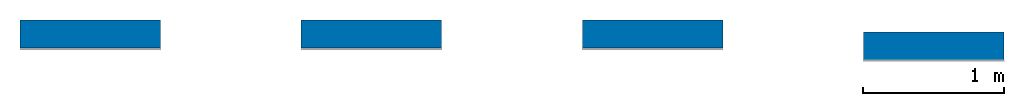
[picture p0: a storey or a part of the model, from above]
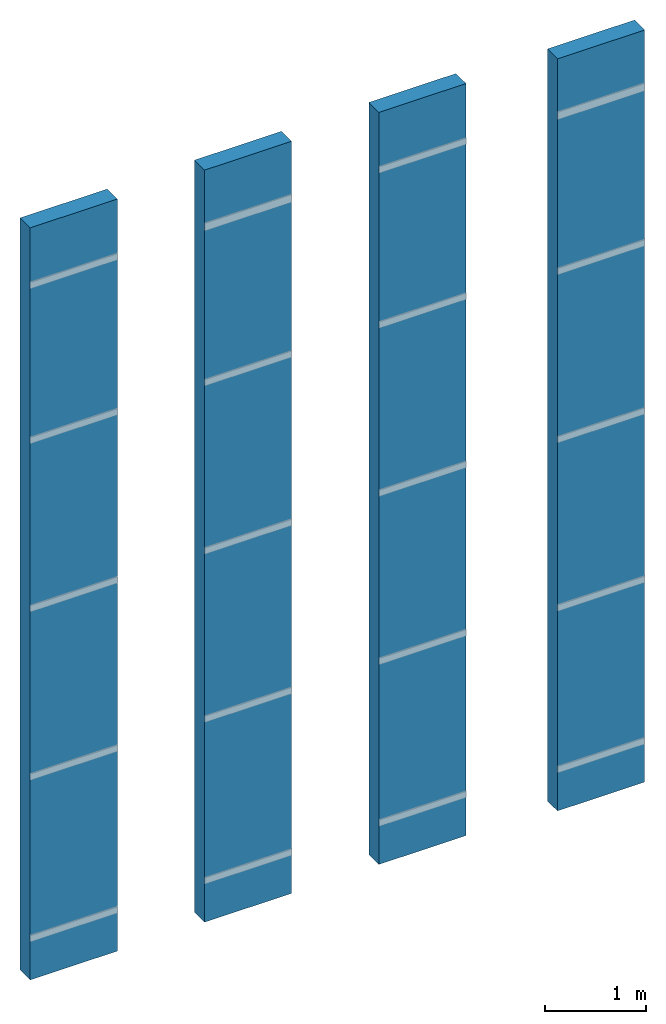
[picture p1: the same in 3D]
Properties of the parts of a building model (IFC2X3), part 1 of 2

# File
Description: ViewDefinition [CoordinationView_V2.0]
Time: 2025-06-20T15:38:34
Written by: The EXPRESS Data Manager Version 5.02.0100.07 : 28 Aug 2013
Made in: 21.1.90.15 - Exporter 21.1.90.15 - Alternate UI 21.1.90.15
Comment: STEP Physical File produced by: The EXPRESS Data Manager Version 5.02.0100.07 : 28 Aug 2013 * Module: EDMstepFileFactory/EDMstandAlone * Creation date: Fri Jun 20 15:38:34 2025 * Host: STB002 * Database: C:\Users\LARISS~1\AppData\Local\Temp\234e31d9-e186-458c-9206-d387dea7a233\f8c6bfc8-973a-4732-9e75-4ff3d9c63b4a\ifc * Database version: 5507 * Database creation date: Fri Jun 20 15:38:33 2025 * Schema: IFC2X3 * Model: DataRepository.ifc * Model creation date: Fri Jun 20 15:38:33 2025 * Header model: DataRepository.ifc_HeaderModel * Header model creation date: Fri Jun 20 15:38:33 2025 * EDMuser: sdai-user * EDMgroup: sdai-group * License ID and type: 5605 : Permanent license. Expiry date: * EDMstepFileFactory options: 020000

# IfcSite, Default
RefLatitude: 42, 24, 53, 508911; RefLongitude: -71, -15, -29, -58837; RefElevation: 0 mm
Pset_ProductRequirements - Category: Project Information

# IfcBuilding
Pset_BuildingCommon - NumberOfStoreys: 1
Pset_ProductRequirements - Category: Project Information

# IfcBuildingStorey: Level:Level 1, Level 1
LongName: Level 1; Elevation: 0 mm
Pset_AirSideSystemInformation - Name: Level 1
Pset_ProductRequirements - Name: Level 1; Category: Levels

# IfcBuildingElementProxy: Wall Sweep:REVIGRÉS-RULE-RB-8X120-SILK-ALLOY, Wall Sweep:REVIGRÉS-RULE-RB-8X120-SILK-ALLOY:180124
In: Level 1
Type - Pset_BuildingElementProxyCommon - Reference: REVIGRÉS-RULE-RB-8X120-SILK-ALLOY
Type - Pset_ManufacturerTypeInformation - Manufacturer: REVIGRÉS
Type - Pset_ProductRequirements - Category: Wall Sweeps
Type - Pset_QuantityTakeOff - Reference: REVIGRÉS-RULE-RB-8X120-SILK-ALLOY
Type - IFC.REVIGRÉS-Dados do fabricante-Wall Sweeps - FabricanteURL: https://www.revigres.pt/; ReferenciaModelo: Rule; Acabamento: SILK; IdentificadorDoOperadorEconomico: 501840856; UrlFabricanteArtigo: https://www.revigres.pt/colecoes/rule; PaisOrigem: Portugal
Type - IFC.REVIGRÉS-Dados de desempenho-Wall Sweeps - Rectilinearidade: ± 0.2% máx.± 0.8 mm; Ortogonalidade: ± 0.2% máx.± 1.5 mm; PlanaridadeDaSuperficie: ± 0.3% máx. ± 1.8 mm; AbsorcaoDeAgua: < 0.05%; ModuloDeRuptura: > 45 N/mm²; ResistenciaAFlexao: >3500 N; ResistenciaAAbrasaoProfunda: < 120 mm³; DilatacaoTermicaLinear: ≤ 8,0x10-6 °C-1; ResistenciaAoChoqueTermico: Resiste; DurabilidadeResistenciaAoGeloDegelo: Resiste; ResistenciaAoEscorregamentoDIN51130: R9; ResistenciaAoEscorregamentoDIN51097: A; ResistenciaAoEscorregamentoENV51097: A; ResistenciaAoDeslizamentoENV12633: Class 1; ResistenciaAoEscorregamentoANSIA1371: ≥0,42; ResistenciaAoEscorregamentoENV12633: Class 1; ResistenciaAsManchas: Class 5; ResistenciaABaixasConcentracoesDeAcidosEAlcalis: Classe LA; ResistenciaAAltasConcentracoesDeAcidosEAlcalis: Classe HA; LibertacaoDeCadmio: 0; LibertacaoDeChumbo: 0
Type - IFC.REVIGRÉS-Dados de especificação-Wall Sweeps - VariacaoTonalidade: 3; NivelDeTrafego: 5; EPavimento: Não; ERevestimento: Sim; EExterno: Sim
Type - IFC.REVIGRÉS-Dados geométricos-Wall Sweeps - AlturaNominal: 10.5 mm; ComprimentoNominal: 8 mm; LarguraNominal: 118.6 mm
Type - IFC.REVIGRÉS-Dados de sustentabilidade-Wall Sweeps - ItemEParcialmenteReciclado: 0; PotencialPrivacaoDeAguaConsumoDeAguaPonderado: 4.5; EnergiaTermicaExportada: 0; ItemENovo: Sim; ItemEReciclado: Não; VidaÚtilEsperada: 50; SubstanciasPerigosas: Não; PotencialDeEsgotamentoAbioticoDosRecursosFosseis: 203; PotencialDeEsgotamentoAbioticoDosRecursosNaoFosseisMineraisEMetais: 0.000701; PotencialDeAquecimentoGlobalBiogenico: -0.48; CombustiveisFosseisComPotencialDeAquecimentoGlobal: 13.9; PotencialDeAquecimentoGlobalUsoDoSoloEMudancaDeUsoDoSolo: 0.0246; PotencialDeEutrofizacaoFraccaoDeNutrientesQueAtingemOCompartimentoFinalDeAguaDoce: 0.000189; PotencialDeEutrofizacaoFraccaoDeNutrientesQueAtingemOCompartimentoFinalMarinho: 0.0122; EnergiaRecuperada: 0.00739; ConsumoDeAguaDoce: 0.113; UtilizacaoLiquidaDeAguaDoce: 0.113; ResiduosPerigososEliminados: 0.00221; ResiduosNaoPerigososEliminados: 1.83; MassaTotalDeResiduosRadioactivosEliminados: 0.000394; EnergiaElectricaExportada: 1.55; MateriaisParaRecuperacaoDeEnergia: 0.00739; MateriaisParaReciclagem: 0.0253; UnidadeEPD: 1 m²
Type - IFC.REVIGRÉS-Dados gerais-Wall Sweeps - Nome: REVIGRÉS-RULE-RB-8x120-SILK-ALLOY; TipoProduto: Prensado a seco: grupo BIa UGL | Grés porcelânico técnico; NumeroDeRegistoDAP: EPD-REV-20240006-CCC1-EN; ReferenciaDAP: -; UrlDOP: -
Pset_BuildingElementProxyCommon - sets with these values: 2
Pset_ProvisionForVoid - Shape: Undefined; Width: 1000 mm; Depth: 1000 mm
IFC.REVIGRÉS-Dados do fabricante-Wall Sweeps - Type: Wall Sweep: REVIGRÉS-RULE-RB-8X120-SILK-ALLOY
IFC.REVIGRÉS-Dados de desempenho-Wall Sweeps - Type: Wall Sweep: REVIGRÉS-RULE-RB-8X120-SILK-ALLOY
IFC.REVIGRÉS-Dados de especificação-Wall Sweeps - Type: Wall Sweep: REVIGRÉS-RULE-RB-8X120-SILK-ALLOY
IFC.REVIGRÉS-Dados geométricos-Wall Sweeps - Type: Wall Sweep: REVIGRÉS-RULE-RB-8X120-SILK-ALLOY
IFC.REVIGRÉS-Dados de sustentabilidade-Wall Sweeps - Type: Wall Sweep: REVIGRÉS-RULE-RB-8X120-SILK-ALLOY

# IfcBuildingElementProxy: Wall Sweep:REVIGRÉS-RULE-RB-8X120-SILK-SMOG, Wall Sweep:REVIGRÉS-RULE-RB-8X120-SILK-SMOG:180131
In: Level 1
Type - Pset_BuildingElementProxyCommon - Reference: REVIGRÉS-RULE-RB-8X120-SILK-SMOG
Type - Pset_ManufacturerTypeInformation - Manufacturer: REVIGRÉS
Type - Pset_ProductRequirements - Category: Wall Sweeps
Type - Pset_QuantityTakeOff - Reference: REVIGRÉS-RULE-RB-8X120-SILK-SMOG
Type - IFC.REVIGRÉS-Dados do fabricante-Wall Sweeps - FabricanteURL: https://www.revigres.pt/; ReferenciaModelo: Rule; Acabamento: SILK; IdentificadorDoOperadorEconomico: 501840856; UrlFabricanteArtigo: https://www.revigres.pt/colecoes/rule; PaisOrigem: Portugal
Type - IFC.REVIGRÉS-Dados de desempenho-Wall Sweeps - Rectilinearidade: ± 0.2% máx.± 0.8 mm; Ortogonalidade: ± 0.2% máx.± 1.5 mm; PlanaridadeDaSuperficie: ± 0.3% máx. ± 1.8 mm; AbsorcaoDeAgua: < 0.05%; ModuloDeRuptura: > 45 N/mm²; ResistenciaAFlexao: >3500 N; ResistenciaAAbrasaoProfunda: < 120 mm³; DilatacaoTermicaLinear: ≤ 8,0x10-6 °C-1; ResistenciaAoChoqueTermico: Resiste; DurabilidadeResistenciaAoGeloDegelo: Resiste; ResistenciaAoEscorregamentoDIN51130: R9; ResistenciaAoEscorregamentoDIN51097: A; ResistenciaAoEscorregamentoENV51097: A; ResistenciaAoDeslizamentoENV12633: Class 1; ResistenciaAoEscorregamentoANSIA1371: ≥0,42; ResistenciaAoEscorregamentoENV12633: Class 1; ResistenciaAsManchas: Class 5; ResistenciaABaixasConcentracoesDeAcidosEAlcalis: Classe LA; ResistenciaAAltasConcentracoesDeAcidosEAlcalis: Classe HA; LibertacaoDeCadmio: 0; LibertacaoDeChumbo: 0
Type - IFC.REVIGRÉS-Dados de especificação-Wall Sweeps - VariacaoTonalidade: 3; NivelDeTrafego: 5; EPavimento: Não; ERevestimento: Sim; EExterno: Sim
Type - IFC.REVIGRÉS-Dados geométricos-Wall Sweeps - AlturaNominal: 10.5 mm; ComprimentoNominal: 8 mm; LarguraNominal: 118.6 mm
Type - IFC.REVIGRÉS-Dados de sustentabilidade-Wall Sweeps - PotencialPrivacaoDeAguaConsumoDeAguaPonderado: 4.5; EnergiaTermicaExportada: 0; ItemENovo: Sim; ItemEParcialmenteReciclado: 0.23; ItemEReciclado: Sim; VidaÚtilEsperada: 50; SubstanciasPerigosas: Não; PotencialDeEsgotamentoAbioticoDosRecursosFosseis: 203; PotencialDeEsgotamentoAbioticoDosRecursosNaoFosseisMineraisEMetais: 0.000701; PotencialDeAquecimentoGlobalBiogenico: -0.48; CombustiveisFosseisComPotencialDeAquecimentoGlobal: 13.9; PotencialDeAquecimentoGlobalUsoDoSoloEMudancaDeUsoDoSolo: 0.0246; PotencialDeEutrofizacaoFraccaoDeNutrientesQueAtingemOCompartimentoFinalDeAguaDoce: 0.000189; PotencialDeEutrofizacaoFraccaoDeNutrientesQueAtingemOCompartimentoFinalMarinho: 0.0122; EnergiaRecuperada: 0.00739; ConsumoDeAguaDoce: 0.113; UtilizacaoLiquidaDeAguaDoce: 0.113; ResiduosPerigososEliminados: 0.00221; ResiduosNaoPerigososEliminados: 1.83; MassaTotalDeResiduosRadioactivosEliminados: 0.000394; EnergiaElectricaExportada: 1.55; MateriaisParaRecuperacaoDeEnergia: 0.00739; MateriaisParaReciclagem: 0.0253; UnidadeEPD: 1 m²
Type - IFC.REVIGRÉS-Dados gerais-Wall Sweeps - Nome: REVIGRÉS-RULE-RB-8x120-SILK-SMOG; TipoProduto: Prensado a seco: grupo BIa UGL | Grés porcelânico técnico; NumeroDeRegistoDAP: EPD-REV-20240006-CCC1-EN; ReferenciaDAP: -; UrlDOP: -
Pset_BuildingElementProxyCommon - sets with these values: 2
Pset_ProvisionForVoid - Shape: Undefined; Width: 1000 mm; Depth: 1000 mm
IFC.REVIGRÉS-Dados do fabricante-Wall Sweeps - Type: Wall Sweep: REVIGRÉS-RULE-RB-8X120-SILK-SMOG
IFC.REVIGRÉS-Dados de desempenho-Wall Sweeps - Type: Wall Sweep: REVIGRÉS-RULE-RB-8X120-SILK-SMOG
IFC.REVIGRÉS-Dados de especificação-Wall Sweeps - Type: Wall Sweep: REVIGRÉS-RULE-RB-8X120-SILK-SMOG
IFC.REVIGRÉS-Dados geométricos-Wall Sweeps - Type: Wall Sweep: REVIGRÉS-RULE-RB-8X120-SILK-SMOG
IFC.REVIGRÉS-Dados de sustentabilidade-Wall Sweeps - Type: Wall Sweep: REVIGRÉS-RULE-RB-8X120-SILK-SMOG

# IfcBuildingElementProxy: Wall Sweep:REVIGRÉS-RULE-RB-8X120-SOFT GRIP-ALLOY, Wall Sweep:REVIGRÉS-RULE-RB-8X120-SOFT GRIP-ALLOY:180112
In: Level 1
Type - Pset_BuildingElementProxyCommon - Reference: REVIGRÉS-RULE-RB-8X120-SOFT GRIP-ALLOY
Type - Pset_ManufacturerTypeInformation - Manufacturer: REVIGRÉS
Type - Pset_ProductRequirements - Category: Wall Sweeps
Type - Pset_QuantityTakeOff - Reference: REVIGRÉS-RULE-RB-8X120-SOFT GRIP-ALLOY
Type - IFC.REVIGRÉS-Dados do fabricante-Wall Sweeps - FabricanteURL: https://www.revigres.pt/; ReferenciaModelo: Rule; Acabamento: SOFT GRIP; IdentificadorDoOperadorEconomico: 501840856; UrlFabricanteArtigo: https://www.revigres.pt/colecoes/rule; PaisOrigem: Portugal
Type - IFC.REVIGRÉS-Dados de desempenho-Wall Sweeps - Rectilinearidade: ± 0.2% máx.± 0.8 mm; Ortogonalidade: ± 0.2% máx.± 1.5 mm; PlanaridadeDaSuperficie: ± 0.3% máx. ± 1.8 mm; AbsorcaoDeAgua: < 0.05%; ModuloDeRuptura: > 45 N/mm²; ResistenciaAFlexao: >3500 N; ResistenciaAAbrasaoProfunda: < 120 mm³; DilatacaoTermicaLinear: ≤ 8,0x10-6 °C-1; ResistenciaAoChoqueTermico: Resiste; DurabilidadeResistenciaAoGeloDegelo: Resiste; ResistenciaAoEscorregamentoDIN51130: R11; ResistenciaAoEscorregamentoDIN51097: B; ResistenciaAoEscorregamentoENV51097: B; ResistenciaAoDeslizamentoENV12633: Class 2; ResistenciaAoEscorregamentoBS7976: >36; ResistenciaAoEscorregamentoANSIA1371: ≥0,42; ResistenciaAoEscorregamentoENV12633: Class 2; ResistenciaAoDeslizamentoBS7976: >36; ResistenciaAsManchas: Class 5; ResistenciaABaixasConcentracoesDeAcidosEAlcalis: Classe LA; ResistenciaAAltasConcentracoesDeAcidosEAlcalis: Classe HA; LibertacaoDeCadmio: 0; LibertacaoDeChumbo: 0
Type - IFC.REVIGRÉS-Dados de especificação-Wall Sweeps - VariacaoTonalidade: 3; NivelDeTrafego: 5; EPavimento: Não; ERevestimento: Sim; EExterno: Sim
Type - IFC.REVIGRÉS-Dados geométricos-Wall Sweeps - AlturaNominal: 10.5 mm; ComprimentoNominal: 8 mm; LarguraNominal: 118.6 mm
Type - IFC.REVIGRÉS-Dados de sustentabilidade-Wall Sweeps - ItemEParcialmenteReciclado: 0; PotencialPrivacaoDeAguaConsumoDeAguaPonderado: 4.5; EnergiaTermicaExportada: 0; ItemENovo: Sim; ItemEReciclado: Não; VidaÚtilEsperada: 50; SubstanciasPerigosas: Não; PotencialDeEsgotamentoAbioticoDosRecursosFosseis: 203; PotencialDeEsgotamentoAbioticoDosRecursosNaoFosseisMineraisEMetais: 0.000701; PotencialDeAquecimentoGlobalBiogenico: -0.48; CombustiveisFosseisComPotencialDeAquecimentoGlobal: 13.9; PotencialDeAquecimentoGlobalUsoDoSoloEMudancaDeUsoDoSolo: 0.0246; PotencialDeEutrofizacaoFraccaoDeNutrientesQueAtingemOCompartimentoFinalDeAguaDoce: 0.000189; PotencialDeEutrofizacaoFraccaoDeNutrientesQueAtingemOCompartimentoFinalMarinho: 0.0122; EnergiaRecuperada: 0.00739; ConsumoDeAguaDoce: 0.113; UtilizacaoLiquidaDeAguaDoce: 0.113; ResiduosPerigososEliminados: 0.00221; ResiduosNaoPerigososEliminados: 1.83; MassaTotalDeResiduosRadioactivosEliminados: 0.000394; EnergiaElectricaExportada: 1.55; MateriaisParaRecuperacaoDeEnergia: 0.00739; MateriaisParaReciclagem: 0.0253; UnidadeEPD: 1 m²
Type - IFC.REVIGRÉS-Dados gerais-Wall Sweeps - Nome: REVIGRÉS-RULE-RB-8x120-SOFT GRIP-ALLOY; TipoProduto: Prensado a seco: grupo BIa UGL | Grés porcelânico técnico; NumeroDeRegistoDAP: EPD-REV-20240006-CCC1-EN; ReferenciaDAP: -; UrlDOP: -
Pset_BuildingElementProxyCommon - sets with these values: 2
Pset_ProvisionForVoid - Shape: Undefined; Width: 1000 mm; Depth: 1000 mm
IFC.REVIGRÉS-Dados do fabricante-Wall Sweeps - Type: Wall Sweep: REVIGRÉS-RULE-RB-8X120-SOFT GRIP-ALLOY
IFC.REVIGRÉS-Dados de desempenho-Wall Sweeps - Type: Wall Sweep: REVIGRÉS-RULE-RB-8X120-SOFT GRIP-ALLOY
IFC.REVIGRÉS-Dados de especificação-Wall Sweeps - Type: Wall Sweep: REVIGRÉS-RULE-RB-8X120-SOFT GRIP-ALLOY
IFC.REVIGRÉS-Dados geométricos-Wall Sweeps - Type: Wall Sweep: REVIGRÉS-RULE-RB-8X120-SOFT GRIP-ALLOY
IFC.REVIGRÉS-Dados de sustentabilidade-Wall Sweeps - Type: Wall Sweep: REVIGRÉS-RULE-RB-8X120-SOFT GRIP-ALLOY

# IfcBuildingElementProxy: Wall Sweep:REVIGRÉS-RULE-RB-8X120-SOFT GRIP-SMOG, Wall Sweep:REVIGRÉS-RULE-RB-8X120-SOFT GRIP-SMOG:180117
In: Level 1
Type - Pset_BuildingElementProxyCommon - Reference: REVIGRÉS-RULE-RB-8X120-SOFT GRIP-SMOG
Type - Pset_ManufacturerTypeInformation - Manufacturer: REVIGRÉS
Type - Pset_ProductRequirements - Category: Wall Sweeps
Type - Pset_QuantityTakeOff - Reference: REVIGRÉS-RULE-RB-8X120-SOFT GRIP-SMOG
Type - IFC.REVIGRÉS-Dados do fabricante-Wall Sweeps - FabricanteURL: https://www.revigres.pt/; ReferenciaModelo: Rule; Acabamento: SOFT GRIP; IdentificadorDoOperadorEconomico: 501840856; UrlFabricanteArtigo: https://www.revigres.pt/colecoes/rule; PaisOrigem: Portugal
Type - IFC.REVIGRÉS-Dados de desempenho-Wall Sweeps - Rectilinearidade: ± 0.2% máx.± 0.8 mm; Ortogonalidade: ± 0.2% máx.± 1.5 mm; PlanaridadeDaSuperficie: ± 0.3% máx. ± 1.8 mm; AbsorcaoDeAgua: < 0.05%; ModuloDeRuptura: > 45 N/mm²; ResistenciaAFlexao: >3500 N; ResistenciaAAbrasaoProfunda: < 120 mm³; DilatacaoTermicaLinear: ≤ 8,0x10-6 °C-1; ResistenciaAoChoqueTermico: Resiste; DurabilidadeResistenciaAoGeloDegelo: Resiste; ResistenciaAoEscorregamentoDIN51130: R11; ResistenciaAoEscorregamentoDIN51097: B; ResistenciaAoEscorregamentoENV51097: B; ResistenciaAoDeslizamentoENV12633: Class 2; ResistenciaAoEscorregamentoBS7976: >36; ResistenciaAoEscorregamentoANSIA1371: ≥0,42; ResistenciaAoEscorregamentoENV12633: Class 2; ResistenciaAoDeslizamentoBS7976: >36; ResistenciaAsManchas: Class 5; ResistenciaABaixasConcentracoesDeAcidosEAlcalis: Classe LA; ResistenciaAAltasConcentracoesDeAcidosEAlcalis: Classe HA; LibertacaoDeCadmio: 0; LibertacaoDeChumbo: 0
Type - IFC.REVIGRÉS-Dados de especificação-Wall Sweeps - VariacaoTonalidade: 3; NivelDeTrafego: 5; EPavimento: Não; ERevestimento: Sim; EExterno: Sim
Type - IFC.REVIGRÉS-Dados geométricos-Wall Sweeps - AlturaNominal: 10.5 mm; ComprimentoNominal: 8 mm; LarguraNominal: 118.6 mm
Type - IFC.REVIGRÉS-Dados de sustentabilidade-Wall Sweeps - PotencialPrivacaoDeAguaConsumoDeAguaPonderado: 4.5; EnergiaTermicaExportada: 0; ItemENovo: Sim; ItemEParcialmenteReciclado: 0.23; ItemEReciclado: Sim; VidaÚtilEsperada: 50; SubstanciasPerigosas: Não; PotencialDeEsgotamentoAbioticoDosRecursosFosseis: 203; PotencialDeEsgotamentoAbioticoDosRecursosNaoFosseisMineraisEMetais: 0.000701; PotencialDeAquecimentoGlobalBiogenico: -0.48; CombustiveisFosseisComPotencialDeAquecimentoGlobal: 13.9; PotencialDeAquecimentoGlobalUsoDoSoloEMudancaDeUsoDoSolo: 0.0246; PotencialDeEutrofizacaoFraccaoDeNutrientesQueAtingemOCompartimentoFinalDeAguaDoce: 0.000189; PotencialDeEutrofizacaoFraccaoDeNutrientesQueAtingemOCompartimentoFinalMarinho: 0.0122; EnergiaRecuperada: 0.00739; ConsumoDeAguaDoce: 0.113; UtilizacaoLiquidaDeAguaDoce: 0.113; ResiduosPerigososEliminados: 0.00221; ResiduosNaoPerigososEliminados: 1.83; MassaTotalDeResiduosRadioactivosEliminados: 0.000394; EnergiaElectricaExportada: 1.55; MateriaisParaRecuperacaoDeEnergia: 0.00739; MateriaisParaReciclagem: 0.0253; UnidadeEPD: 1 m²
Type - IFC.REVIGRÉS-Dados gerais-Wall Sweeps - Nome: REVIGRÉS-RULE-RB-8x120-SOFT GRIP-SMOG; TipoProduto: Prensado a seco: grupo BIa UGL | Grés porcelânico técnico; NumeroDeRegistoDAP: EPD-REV-20240006-CCC1-EN; ReferenciaDAP: -; UrlDOP: -
Pset_BuildingElementProxyCommon - sets with these values: 2
Pset_ProvisionForVoid - Shape: Undefined; Width: 1000 mm; Depth: 1000 mm
IFC.REVIGRÉS-Dados do fabricante-Wall Sweeps - Type: Wall Sweep: REVIGRÉS-RULE-RB-8X120-SOFT GRIP-SMOG
IFC.REVIGRÉS-Dados de desempenho-Wall Sweeps - Type: Wall Sweep: REVIGRÉS-RULE-RB-8X120-SOFT GRIP-SMOG
IFC.REVIGRÉS-Dados de especificação-Wall Sweeps - Type: Wall Sweep: REVIGRÉS-RULE-RB-8X120-SOFT GRIP-SMOG
IFC.REVIGRÉS-Dados geométricos-Wall Sweeps - Type: Wall Sweep: REVIGRÉS-RULE-RB-8X120-SOFT GRIP-SMOG
IFC.REVIGRÉS-Dados de sustentabilidade-Wall Sweeps - Type: Wall Sweep: REVIGRÉS-RULE-RB-8X120-SOFT GRIP-SMOG

# IfcBuildingElementProxy: Wall Sweep:REVIGRÉS-RULE-RB-8X45-SILK-ALLOY, Wall Sweep:REVIGRÉS-RULE-RB-8X45-SILK-ALLOY:180121
In: Level 1
Type - Pset_BuildingElementProxyCommon - Reference: REVIGRÉS-RULE-RB-8X45-SILK-ALLOY
Type - Pset_ManufacturerTypeInformation - Manufacturer: REVIGRÉS
Type - Pset_ProductRequirements - Category: Wall Sweeps
Type - Pset_QuantityTakeOff - Reference: REVIGRÉS-RULE-RB-8X45-SILK-ALLOY
Type - IFC.REVIGRÉS-Dados do fabricante-Wall Sweeps - FabricanteURL: https://www.revigres.pt/; ReferenciaModelo: Rule; Acabamento: SILK; IdentificadorDoOperadorEconomico: 501840856; UrlFabricanteArtigo: https://www.revigres.pt/colecoes/rule; PaisOrigem: Portugal
Type - IFC.REVIGRÉS-Dados de desempenho-Wall Sweeps - Rectilinearidade: ± 0.2% máx.± 0.8 mm; Ortogonalidade: ± 0.2% máx.± 1.5 mm; PlanaridadeDaSuperficie: ± 0.3% máx. ± 1.8 mm; AbsorcaoDeAgua: < 0.05%; ModuloDeRuptura: > 45 N/mm²; ResistenciaAFlexao: >3500 N; ResistenciaAAbrasaoProfunda: < 120 mm³; DilatacaoTermicaLinear: ≤ 8,0x10-6 °C-1; ResistenciaAoChoqueTermico: Resiste; DurabilidadeResistenciaAoGeloDegelo: Resiste; ResistenciaAoEscorregamentoDIN51130: R9; ResistenciaAoEscorregamentoDIN51097: A; ResistenciaAoEscorregamentoENV51097: A; ResistenciaAoDeslizamentoENV12633: Class 1; ResistenciaAoEscorregamentoANSIA1371: ≥0,42; ResistenciaAoEscorregamentoENV12633: Class 1; ResistenciaAsManchas: Class 5; ResistenciaABaixasConcentracoesDeAcidosEAlcalis: Classe LA; ResistenciaAAltasConcentracoesDeAcidosEAlcalis: Classe HA; LibertacaoDeCadmio: 0; LibertacaoDeChumbo: 0
Type - IFC.REVIGRÉS-Dados de especificação-Wall Sweeps - VariacaoTonalidade: 3; NivelDeTrafego: 5; EPavimento: Não; ERevestimento: Sim; EExterno: Sim
Type - IFC.REVIGRÉS-Dados geométricos-Wall Sweeps - AlturaNominal: 10.5 mm; ComprimentoNominal: 8 mm; LarguraNominal: 44.35 mm
Type - IFC.REVIGRÉS-Dados de sustentabilidade-Wall Sweeps - ItemEParcialmenteReciclado: 0; PotencialPrivacaoDeAguaConsumoDeAguaPonderado: 4.5; EnergiaTermicaExportada: 0; ItemENovo: Sim; ItemEReciclado: Não; VidaÚtilEsperada: 50; SubstanciasPerigosas: Não; PotencialDeEsgotamentoAbioticoDosRecursosFosseis: 203; PotencialDeEsgotamentoAbioticoDosRecursosNaoFosseisMineraisEMetais: 0.000701; PotencialDeAquecimentoGlobalBiogenico: -0.48; CombustiveisFosseisComPotencialDeAquecimentoGlobal: 13.9; PotencialDeAquecimentoGlobalUsoDoSoloEMudancaDeUsoDoSolo: 0.0246; PotencialDeEutrofizacaoFraccaoDeNutrientesQueAtingemOCompartimentoFinalDeAguaDoce: 0.000189; PotencialDeEutrofizacaoFraccaoDeNutrientesQueAtingemOCompartimentoFinalMarinho: 0.0122; EnergiaRecuperada: 0.00739; ConsumoDeAguaDoce: 0.113; UtilizacaoLiquidaDeAguaDoce: 0.113; ResiduosPerigososEliminados: 0.00221; ResiduosNaoPerigososEliminados: 1.83; MassaTotalDeResiduosRadioactivosEliminados: 0.000394; EnergiaElectricaExportada: 1.55; MateriaisParaRecuperacaoDeEnergia: 0.00739; MateriaisParaReciclagem: 0.0253; UnidadeEPD: 1 m²
Type - IFC.REVIGRÉS-Dados gerais-Wall Sweeps - Nome: REVIGRÉS-RULE-RB-8x45-SILK-ALLOY; TipoProduto: Prensado a seco: grupo BIa UGL | Grés porcelânico técnico; NumeroDeRegistoDAP: EPD-REV-20240006-CCC1-EN; ReferenciaDAP: -; UrlDOP: -
Pset_BuildingElementProxyCommon - sets with these values: 2
Pset_ProvisionForVoid - Shape: Undefined; Width: 1000 mm; Depth: 1000 mm
IFC.REVIGRÉS-Dados do fabricante-Wall Sweeps - Type: Wall Sweep: REVIGRÉS-RULE-RB-8X45-SILK-ALLOY
IFC.REVIGRÉS-Dados de desempenho-Wall Sweeps - Type: Wall Sweep: REVIGRÉS-RULE-RB-8X45-SILK-ALLOY
IFC.REVIGRÉS-Dados de especificação-Wall Sweeps - Type: Wall Sweep: REVIGRÉS-RULE-RB-8X45-SILK-ALLOY
IFC.REVIGRÉS-Dados geométricos-Wall Sweeps - Type: Wall Sweep: REVIGRÉS-RULE-RB-8X45-SILK-ALLOY
IFC.REVIGRÉS-Dados de sustentabilidade-Wall Sweeps - Type: Wall Sweep: REVIGRÉS-RULE-RB-8X45-SILK-ALLOY

# IfcBuildingElementProxy: Wall Sweep:REVIGRÉS-RULE-RB-8X45-SILK-SMOG, Wall Sweep:REVIGRÉS-RULE-RB-8X45-SILK-SMOG:180128
In: Level 1
Type - Pset_BuildingElementProxyCommon - Reference: REVIGRÉS-RULE-RB-8X45-SILK-SMOG
Type - Pset_ManufacturerTypeInformation - Manufacturer: REVIGRÉS
Type - Pset_ProductRequirements - Category: Wall Sweeps
Type - Pset_QuantityTakeOff - Reference: REVIGRÉS-RULE-RB-8X45-SILK-SMOG
Type - IFC.REVIGRÉS-Dados do fabricante-Wall Sweeps - FabricanteURL: https://www.revigres.pt/; ReferenciaModelo: Rule; Acabamento: SILK; IdentificadorDoOperadorEconomico: 501840856; UrlFabricanteArtigo: https://www.revigres.pt/colecoes/rule; PaisOrigem: Portugal
Type - IFC.REVIGRÉS-Dados de desempenho-Wall Sweeps - Rectilinearidade: ± 0.2% máx.± 0.8 mm; Ortogonalidade: ± 0.2% máx.± 1.5 mm; PlanaridadeDaSuperficie: ± 0.3% máx. ± 1.8 mm; AbsorcaoDeAgua: < 0.05%; ModuloDeRuptura: > 45 N/mm²; ResistenciaAFlexao: >3500 N; ResistenciaAAbrasaoProfunda: < 120 mm³; DilatacaoTermicaLinear: ≤ 8,0x10-6 °C-1; ResistenciaAoChoqueTermico: Resiste; DurabilidadeResistenciaAoGeloDegelo: Resiste; ResistenciaAoEscorregamentoDIN51130: R9; ResistenciaAoEscorregamentoDIN51097: A; ResistenciaAoEscorregamentoENV51097: A; ResistenciaAoDeslizamentoENV12633: Class 1; ResistenciaAoEscorregamentoANSIA1371: ≥0,42; ResistenciaAoEscorregamentoENV12633: Class 1; ResistenciaAsManchas: Class 5; ResistenciaABaixasConcentracoesDeAcidosEAlcalis: Classe LA; ResistenciaAAltasConcentracoesDeAcidosEAlcalis: Classe HA; LibertacaoDeCadmio: 0; LibertacaoDeChumbo: 0
Type - IFC.REVIGRÉS-Dados de especificação-Wall Sweeps - VariacaoTonalidade: 3; NivelDeTrafego: 5; EPavimento: Não; ERevestimento: Sim; EExterno: Sim
Type - IFC.REVIGRÉS-Dados geométricos-Wall Sweeps - AlturaNominal: 10.5 mm; ComprimentoNominal: 8 mm; LarguraNominal: 44.35 mm
Type - IFC.REVIGRÉS-Dados de sustentabilidade-Wall Sweeps - PotencialPrivacaoDeAguaConsumoDeAguaPonderado: 4.5; EnergiaTermicaExportada: 0; ItemENovo: Sim; ItemEParcialmenteReciclado: 0.23; ItemEReciclado: Sim; VidaÚtilEsperada: 50; SubstanciasPerigosas: Não; PotencialDeEsgotamentoAbioticoDosRecursosFosseis: 203; PotencialDeEsgotamentoAbioticoDosRecursosNaoFosseisMineraisEMetais: 0.000701; PotencialDeAquecimentoGlobalBiogenico: -0.48; CombustiveisFosseisComPotencialDeAquecimentoGlobal: 13.9; PotencialDeAquecimentoGlobalUsoDoSoloEMudancaDeUsoDoSolo: 0.0246; PotencialDeEutrofizacaoFraccaoDeNutrientesQueAtingemOCompartimentoFinalDeAguaDoce: 0.000189; PotencialDeEutrofizacaoFraccaoDeNutrientesQueAtingemOCompartimentoFinalMarinho: 0.0122; EnergiaRecuperada: 0.00739; ConsumoDeAguaDoce: 0.113; UtilizacaoLiquidaDeAguaDoce: 0.113; ResiduosPerigososEliminados: 0.00221; ResiduosNaoPerigososEliminados: 1.83; MassaTotalDeResiduosRadioactivosEliminados: 0.000394; EnergiaElectricaExportada: 1.55; MateriaisParaRecuperacaoDeEnergia: 0.00739; MateriaisParaReciclagem: 0.0253; UnidadeEPD: 1 m²
Type - IFC.REVIGRÉS-Dados gerais-Wall Sweeps - Nome: REVIGRÉS-RULE-RB-8x45-SILK-SMOG; TipoProduto: Prensado a seco: grupo BIa UGL | Grés porcelânico técnico; NumeroDeRegistoDAP: EPD-REV-20240006-CCC1-EN; ReferenciaDAP: -; UrlDOP: -
Pset_BuildingElementProxyCommon - sets with these values: 2
Pset_ProvisionForVoid - Shape: Undefined; Width: 1000 mm; Depth: 1000 mm
IFC.REVIGRÉS-Dados do fabricante-Wall Sweeps - Type: Wall Sweep: REVIGRÉS-RULE-RB-8X45-SILK-SMOG
IFC.REVIGRÉS-Dados de desempenho-Wall Sweeps - Type: Wall Sweep: REVIGRÉS-RULE-RB-8X45-SILK-SMOG
IFC.REVIGRÉS-Dados de especificação-Wall Sweeps - Type: Wall Sweep: REVIGRÉS-RULE-RB-8X45-SILK-SMOG
IFC.REVIGRÉS-Dados geométricos-Wall Sweeps - Type: Wall Sweep: REVIGRÉS-RULE-RB-8X45-SILK-SMOG
IFC.REVIGRÉS-Dados de sustentabilidade-Wall Sweeps - Type: Wall Sweep: REVIGRÉS-RULE-RB-8X45-SILK-SMOG

# IfcBuildingElementProxy: Wall Sweep:REVIGRÉS-RULE-RB-8X45-SOFT GRIP-ALLOY, Wall Sweep:REVIGRÉS-RULE-RB-8X45-SOFT GRIP-ALLOY:180109
In: Level 1
Type - Pset_BuildingElementProxyCommon - Reference: REVIGRÉS-RULE-RB-8X45-SOFT GRIP-ALLOY
Type - Pset_ManufacturerTypeInformation - Manufacturer: REVIGRÉS
Type - Pset_ProductRequirements - Category: Wall Sweeps
Type - Pset_QuantityTakeOff - Reference: REVIGRÉS-RULE-RB-8X45-SOFT GRIP-ALLOY
Type - IFC.REVIGRÉS-Dados do fabricante-Wall Sweeps - FabricanteURL: https://www.revigres.pt/; ReferenciaModelo: Rule; Acabamento: SOFT GRIP; IdentificadorDoOperadorEconomico: 501840856; UrlFabricanteArtigo: https://www.revigres.pt/colecoes/rule; PaisOrigem: Portugal
Type - IFC.REVIGRÉS-Dados de desempenho-Wall Sweeps - Rectilinearidade: ± 0.2% máx.± 0.8 mm; Ortogonalidade: ± 0.2% máx.± 1.5 mm; PlanaridadeDaSuperficie: ± 0.3% máx. ± 1.8 mm; AbsorcaoDeAgua: < 0.05%; ModuloDeRuptura: > 45 N/mm²; ResistenciaAFlexao: >3500 N; ResistenciaAAbrasaoProfunda: < 120 mm³; DilatacaoTermicaLinear: ≤ 8,0x10-6 °C-1; ResistenciaAoChoqueTermico: Resiste; DurabilidadeResistenciaAoGeloDegelo: Resiste; ResistenciaAoEscorregamentoDIN51130: R11; ResistenciaAoEscorregamentoDIN51097: B; ResistenciaAoEscorregamentoENV51097: B; ResistenciaAoDeslizamentoENV12633: Class 2; ResistenciaAoEscorregamentoBS7976: >36; ResistenciaAoEscorregamentoANSIA1371: ≥0,42; ResistenciaAoEscorregamentoENV12633: Class 2; ResistenciaAoDeslizamentoBS7976: >36; ResistenciaAsManchas: Class 5; ResistenciaABaixasConcentracoesDeAcidosEAlcalis: Classe LA; ResistenciaAAltasConcentracoesDeAcidosEAlcalis: Classe HA; LibertacaoDeCadmio: 0; LibertacaoDeChumbo: 0
Type - IFC.REVIGRÉS-Dados de especificação-Wall Sweeps - VariacaoTonalidade: 3; NivelDeTrafego: 5; EPavimento: Não; ERevestimento: Sim; EExterno: Sim
Type - IFC.REVIGRÉS-Dados geométricos-Wall Sweeps - AlturaNominal: 10.5 mm; ComprimentoNominal: 8 mm; LarguraNominal: 44.35 mm
Type - IFC.REVIGRÉS-Dados de sustentabilidade-Wall Sweeps - ItemEParcialmenteReciclado: 0; PotencialPrivacaoDeAguaConsumoDeAguaPonderado: 4.5; EnergiaTermicaExportada: 0; ItemENovo: Sim; ItemEReciclado: Não; VidaÚtilEsperada: 50; SubstanciasPerigosas: Não; PotencialDeEsgotamentoAbioticoDosRecursosFosseis: 203; PotencialDeEsgotamentoAbioticoDosRecursosNaoFosseisMineraisEMetais: 0.000701; PotencialDeAquecimentoGlobalBiogenico: -0.48; CombustiveisFosseisComPotencialDeAquecimentoGlobal: 13.9; PotencialDeAquecimentoGlobalUsoDoSoloEMudancaDeUsoDoSolo: 0.0246; PotencialDeEutrofizacaoFraccaoDeNutrientesQueAtingemOCompartimentoFinalDeAguaDoce: 0.000189; PotencialDeEutrofizacaoFraccaoDeNutrientesQueAtingemOCompartimentoFinalMarinho: 0.0122; EnergiaRecuperada: 0.00739; ConsumoDeAguaDoce: 0.113; UtilizacaoLiquidaDeAguaDoce: 0.113; ResiduosPerigososEliminados: 0.00221; ResiduosNaoPerigososEliminados: 1.83; MassaTotalDeResiduosRadioactivosEliminados: 0.000394; EnergiaElectricaExportada: 1.55; MateriaisParaRecuperacaoDeEnergia: 0.00739; MateriaisParaReciclagem: 0.0253; UnidadeEPD: 1 m²
Type - IFC.REVIGRÉS-Dados gerais-Wall Sweeps - Nome: REVIGRÉS-RULE-RB-8x45-SOFT GRIP-ALLOY; TipoProduto: Prensado a seco: grupo BIa UGL | Grés porcelânico técnico; NumeroDeRegistoDAP: EPD-REV-20240006-CCC1-EN; ReferenciaDAP: -; UrlDOP: -
Pset_BuildingElementProxyCommon - sets with these values: 2
Pset_ProvisionForVoid - Shape: Undefined; Width: 1000 mm; Depth: 1000 mm
IFC.REVIGRÉS-Dados do fabricante-Wall Sweeps - Type: Wall Sweep: REVIGRÉS-RULE-RB-8X45-SOFT GRIP-ALLOY
IFC.REVIGRÉS-Dados de desempenho-Wall Sweeps - Type: Wall Sweep: REVIGRÉS-RULE-RB-8X45-SOFT GRIP-ALLOY
IFC.REVIGRÉS-Dados de especificação-Wall Sweeps - Type: Wall Sweep: REVIGRÉS-RULE-RB-8X45-SOFT GRIP-ALLOY
IFC.REVIGRÉS-Dados geométricos-Wall Sweeps - Type: Wall Sweep: REVIGRÉS-RULE-RB-8X45-SOFT GRIP-ALLOY
IFC.REVIGRÉS-Dados de sustentabilidade-Wall Sweeps - Type: Wall Sweep: REVIGRÉS-RULE-RB-8X45-SOFT GRIP-ALLOY

# IfcBuildingElementProxy: Wall Sweep:REVIGRÉS-RULE-RB-8X45-SOFT GRIP-SMOG, Wall Sweep:REVIGRÉS-RULE-RB-8X45-SOFT GRIP-SMOG:180126
In: Level 1
Type - Pset_BuildingElementProxyCommon - Reference: REVIGRÉS-RULE-RB-8X45-SOFT GRIP-SMOG
Type - Pset_ManufacturerTypeInformation - Manufacturer: REVIGRÉS
Type - Pset_ProductRequirements - Category: Wall Sweeps
Type - Pset_QuantityTakeOff - Reference: REVIGRÉS-RULE-RB-8X45-SOFT GRIP-SMOG
Type - IFC.REVIGRÉS-Dados do fabricante-Wall Sweeps - FabricanteURL: https://www.revigres.pt/; ReferenciaModelo: Rule; Acabamento: SOFT GRIP; IdentificadorDoOperadorEconomico: 501840856; UrlFabricanteArtigo: https://www.revigres.pt/colecoes/rule; PaisOrigem: Portugal
Type - IFC.REVIGRÉS-Dados de desempenho-Wall Sweeps - Rectilinearidade: ± 0.2% máx.± 0.8 mm; Ortogonalidade: ± 0.2% máx.± 1.5 mm; PlanaridadeDaSuperficie: ± 0.3% máx. ± 1.8 mm; AbsorcaoDeAgua: < 0.05%; ModuloDeRuptura: > 45 N/mm²; ResistenciaAFlexao: >3500 N; ResistenciaAAbrasaoProfunda: < 120 mm³; DilatacaoTermicaLinear: ≤ 8,0x10-6 °C-1; ResistenciaAoChoqueTermico: Resiste; DurabilidadeResistenciaAoGeloDegelo: Resiste; ResistenciaAoEscorregamentoDIN51130: R11; ResistenciaAoEscorregamentoDIN51097: B; ResistenciaAoEscorregamentoENV51097: B; ResistenciaAoDeslizamentoENV12633: Class 2; ResistenciaAoEscorregamentoBS7976: >36; ResistenciaAoEscorregamentoANSIA1371: ≥0,42; ResistenciaAoEscorregamentoENV12633: Class 2; ResistenciaAoDeslizamentoBS7976: >36; ResistenciaAsManchas: Class 5; ResistenciaABaixasConcentracoesDeAcidosEAlcalis: Classe LA; ResistenciaAAltasConcentracoesDeAcidosEAlcalis: Classe HA; LibertacaoDeCadmio: 0; LibertacaoDeChumbo: 0
Type - IFC.REVIGRÉS-Dados de especificação-Wall Sweeps - VariacaoTonalidade: 3; NivelDeTrafego: 5; EPavimento: Não; ERevestimento: Sim; EExterno: Sim
Type - IFC.REVIGRÉS-Dados geométricos-Wall Sweeps - AlturaNominal: 10.5 mm; ComprimentoNominal: 8 mm; LarguraNominal: 44.35 mm
Type - IFC.REVIGRÉS-Dados de sustentabilidade-Wall Sweeps - PotencialPrivacaoDeAguaConsumoDeAguaPonderado: 4.5; EnergiaTermicaExportada: 0; ItemENovo: Sim; ItemEParcialmenteReciclado: 0.23; ItemEReciclado: Sim; VidaÚtilEsperada: 50; SubstanciasPerigosas: Não; PotencialDeEsgotamentoAbioticoDosRecursosFosseis: 203; PotencialDeEsgotamentoAbioticoDosRecursosNaoFosseisMineraisEMetais: 0.000701; PotencialDeAquecimentoGlobalBiogenico: -0.48; CombustiveisFosseisComPotencialDeAquecimentoGlobal: 13.9; PotencialDeAquecimentoGlobalUsoDoSoloEMudancaDeUsoDoSolo: 0.0246; PotencialDeEutrofizacaoFraccaoDeNutrientesQueAtingemOCompartimentoFinalDeAguaDoce: 0.000189; PotencialDeEutrofizacaoFraccaoDeNutrientesQueAtingemOCompartimentoFinalMarinho: 0.0122; EnergiaRecuperada: 0.00739; ConsumoDeAguaDoce: 0.113; UtilizacaoLiquidaDeAguaDoce: 0.113; ResiduosPerigososEliminados: 0.00221; ResiduosNaoPerigososEliminados: 1.83; MassaTotalDeResiduosRadioactivosEliminados: 0.000394; EnergiaElectricaExportada: 1.55; MateriaisParaRecuperacaoDeEnergia: 0.00739; MateriaisParaReciclagem: 0.0253; UnidadeEPD: 1 m²
Type - IFC.REVIGRÉS-Dados gerais-Wall Sweeps - Nome: REVIGRÉS-RULE-RB-8x45-SOFT GRIP-SMOG; TipoProduto: Prensado a seco: grupo BIa UGL | Grés porcelânico técnico; NumeroDeRegistoDAP: EPD-REV-20240006-CCC1-EN; ReferenciaDAP: -; UrlDOP: -
Pset_BuildingElementProxyCommon - sets with these values: 2
Pset_ProvisionForVoid - Shape: Undefined; Width: 1000 mm; Depth: 1000 mm
IFC.REVIGRÉS-Dados do fabricante-Wall Sweeps - Type: Wall Sweep: REVIGRÉS-RULE-RB-8X45-SOFT GRIP-SMOG
IFC.REVIGRÉS-Dados de desempenho-Wall Sweeps - Type: Wall Sweep: REVIGRÉS-RULE-RB-8X45-SOFT GRIP-SMOG
IFC.REVIGRÉS-Dados de especificação-Wall Sweeps - Type: Wall Sweep: REVIGRÉS-RULE-RB-8X45-SOFT GRIP-SMOG
IFC.REVIGRÉS-Dados geométricos-Wall Sweeps - Type: Wall Sweep: REVIGRÉS-RULE-RB-8X45-SOFT GRIP-SMOG
IFC.REVIGRÉS-Dados de sustentabilidade-Wall Sweeps - Type: Wall Sweep: REVIGRÉS-RULE-RB-8X45-SOFT GRIP-SMOG

# IfcBuildingElementProxy: Wall Sweep:REVIGRÉS-RULE-RB-8X60-SILK-ALLOY, Wall Sweep:REVIGRÉS-RULE-RB-8X60-SILK-ALLOY:180122
In: Level 1
Type - Pset_BuildingElementProxyCommon - Reference: REVIGRÉS-RULE-RB-8X60-SILK-ALLOY
Type - Pset_ManufacturerTypeInformation - Manufacturer: REVIGRÉS
Type - Pset_ProductRequirements - Category: Wall Sweeps
Type - Pset_QuantityTakeOff - Reference: REVIGRÉS-RULE-RB-8X60-SILK-ALLOY
Type - IFC.REVIGRÉS-Dados do fabricante-Wall Sweeps - FabricanteURL: https://www.revigres.pt/; ReferenciaModelo: Rule; Acabamento: SILK; IdentificadorDoOperadorEconomico: 501840856; UrlFabricanteArtigo: https://www.revigres.pt/colecoes/rule; PaisOrigem: Portugal
Type - IFC.REVIGRÉS-Dados de desempenho-Wall Sweeps - Rectilinearidade: ± 0.2% máx.± 0.8 mm; Ortogonalidade: ± 0.2% máx.± 1.5 mm; PlanaridadeDaSuperficie: ± 0.3% máx. ± 1.8 mm; AbsorcaoDeAgua: < 0.05%; ModuloDeRuptura: > 45 N/mm²; ResistenciaAFlexao: >3500 N; ResistenciaAAbrasaoProfunda: < 120 mm³; DilatacaoTermicaLinear: ≤ 8,0x10-6 °C-1; ResistenciaAoChoqueTermico: Resiste; DurabilidadeResistenciaAoGeloDegelo: Resiste; ResistenciaAoEscorregamentoDIN51130: R9; ResistenciaAoEscorregamentoDIN51097: A; ResistenciaAoEscorregamentoENV51097: A; ResistenciaAoDeslizamentoENV12633: Class 1; ResistenciaAoEscorregamentoANSIA1371: ≥0,42; ResistenciaAoEscorregamentoENV12633: Class 1; ResistenciaAsManchas: Class 5; ResistenciaABaixasConcentracoesDeAcidosEAlcalis: Classe LA; ResistenciaAAltasConcentracoesDeAcidosEAlcalis: Classe HA; LibertacaoDeCadmio: 0; LibertacaoDeChumbo: 0
Type - IFC.REVIGRÉS-Dados de especificação-Wall Sweeps - VariacaoTonalidade: 3; NivelDeTrafego: 5; EPavimento: Não; ERevestimento: Sim; EExterno: Sim
Type - IFC.REVIGRÉS-Dados geométricos-Wall Sweeps - AlturaNominal: 10.5 mm; ComprimentoNominal: 8 mm; LarguraNominal: 59.2 mm
Type - IFC.REVIGRÉS-Dados de sustentabilidade-Wall Sweeps - ItemEParcialmenteReciclado: 0; PotencialPrivacaoDeAguaConsumoDeAguaPonderado: 4.5; EnergiaTermicaExportada: 0; ItemENovo: Sim; ItemEReciclado: Não; VidaÚtilEsperada: 50; SubstanciasPerigosas: Não; PotencialDeEsgotamentoAbioticoDosRecursosFosseis: 203; PotencialDeEsgotamentoAbioticoDosRecursosNaoFosseisMineraisEMetais: 0.000701; PotencialDeAquecimentoGlobalBiogenico: -0.48; CombustiveisFosseisComPotencialDeAquecimentoGlobal: 13.9; PotencialDeAquecimentoGlobalUsoDoSoloEMudancaDeUsoDoSolo: 0.0246; PotencialDeEutrofizacaoFraccaoDeNutrientesQueAtingemOCompartimentoFinalDeAguaDoce: 0.000189; PotencialDeEutrofizacaoFraccaoDeNutrientesQueAtingemOCompartimentoFinalMarinho: 0.0122; EnergiaRecuperada: 0.00739; ConsumoDeAguaDoce: 0.113; UtilizacaoLiquidaDeAguaDoce: 0.113; ResiduosPerigososEliminados: 0.00221; ResiduosNaoPerigososEliminados: 1.83; MassaTotalDeResiduosRadioactivosEliminados: 0.000394; EnergiaElectricaExportada: 1.55; MateriaisParaRecuperacaoDeEnergia: 0.00739; MateriaisParaReciclagem: 0.0253; UnidadeEPD: 1 m²
Type - IFC.REVIGRÉS-Dados gerais-Wall Sweeps - Nome: REVIGRÉS-RULE-RB-8x60-SILK-ALLOY; TipoProduto: Prensado a seco: grupo BIa UGL | Grés porcelânico técnico; NumeroDeRegistoDAP: EPD-REV-20240006-CCC1-EN; ReferenciaDAP: -; UrlDOP: -
Pset_BuildingElementProxyCommon - sets with these values: 2
Pset_ProvisionForVoid - Shape: Undefined; Width: 1000 mm; Depth: 1000 mm
IFC.REVIGRÉS-Dados do fabricante-Wall Sweeps - Type: Wall Sweep: REVIGRÉS-RULE-RB-8X60-SILK-ALLOY
IFC.REVIGRÉS-Dados de desempenho-Wall Sweeps - Type: Wall Sweep: REVIGRÉS-RULE-RB-8X60-SILK-ALLOY
IFC.REVIGRÉS-Dados de especificação-Wall Sweeps - Type: Wall Sweep: REVIGRÉS-RULE-RB-8X60-SILK-ALLOY
IFC.REVIGRÉS-Dados geométricos-Wall Sweeps - Type: Wall Sweep: REVIGRÉS-RULE-RB-8X60-SILK-ALLOY
IFC.REVIGRÉS-Dados de sustentabilidade-Wall Sweeps - Type: Wall Sweep: REVIGRÉS-RULE-RB-8X60-SILK-ALLOY

# IfcBuildingElementProxy: Wall Sweep:REVIGRÉS-RULE-RB-8X60-SILK-SMOG, Wall Sweep:REVIGRÉS-RULE-RB-8X60-SILK-SMOG:180129
In: Level 1
Type - Pset_BuildingElementProxyCommon - Reference: REVIGRÉS-RULE-RB-8X60-SILK-SMOG
Type - Pset_ManufacturerTypeInformation - Manufacturer: REVIGRÉS
Type - Pset_ProductRequirements - Category: Wall Sweeps
Type - Pset_QuantityTakeOff - Reference: REVIGRÉS-RULE-RB-8X60-SILK-SMOG
Type - IFC.REVIGRÉS-Dados do fabricante-Wall Sweeps - FabricanteURL: https://www.revigres.pt/; ReferenciaModelo: Rule; Acabamento: SILK; IdentificadorDoOperadorEconomico: 501840856; UrlFabricanteArtigo: https://www.revigres.pt/colecoes/rule; PaisOrigem: Portugal
Type - IFC.REVIGRÉS-Dados de desempenho-Wall Sweeps - Rectilinearidade: ± 0.2% máx.± 0.8 mm; Ortogonalidade: ± 0.2% máx.± 1.5 mm; PlanaridadeDaSuperficie: ± 0.3% máx. ± 1.8 mm; AbsorcaoDeAgua: < 0.05%; ModuloDeRuptura: > 45 N/mm²; ResistenciaAFlexao: >3500 N; ResistenciaAAbrasaoProfunda: < 120 mm³; DilatacaoTermicaLinear: ≤ 8,0x10-6 °C-1; ResistenciaAoChoqueTermico: Resiste; DurabilidadeResistenciaAoGeloDegelo: Resiste; ResistenciaAoEscorregamentoDIN51130: R9; ResistenciaAoEscorregamentoDIN51097: A; ResistenciaAoEscorregamentoENV51097: A; ResistenciaAoDeslizamentoENV12633: Class 1; ResistenciaAoEscorregamentoANSIA1371: ≥0,42; ResistenciaAoEscorregamentoENV12633: Class 1; ResistenciaAsManchas: Class 5; ResistenciaABaixasConcentracoesDeAcidosEAlcalis: Classe LA; ResistenciaAAltasConcentracoesDeAcidosEAlcalis: Classe HA; LibertacaoDeCadmio: 0; LibertacaoDeChumbo: 0
Type - IFC.REVIGRÉS-Dados de especificação-Wall Sweeps - VariacaoTonalidade: 3; NivelDeTrafego: 5; EPavimento: Não; ERevestimento: Sim; EExterno: Sim
Type - IFC.REVIGRÉS-Dados geométricos-Wall Sweeps - AlturaNominal: 10.5 mm; ComprimentoNominal: 8 mm; LarguraNominal: 59.2 mm
Type - IFC.REVIGRÉS-Dados de sustentabilidade-Wall Sweeps - PotencialPrivacaoDeAguaConsumoDeAguaPonderado: 4.5; EnergiaTermicaExportada: 0; ItemENovo: Sim; ItemEParcialmenteReciclado: 0.23; ItemEReciclado: Sim; VidaÚtilEsperada: 50; SubstanciasPerigosas: Não; PotencialDeEsgotamentoAbioticoDosRecursosFosseis: 203; PotencialDeEsgotamentoAbioticoDosRecursosNaoFosseisMineraisEMetais: 0.000701; PotencialDeAquecimentoGlobalBiogenico: -0.48; CombustiveisFosseisComPotencialDeAquecimentoGlobal: 13.9; PotencialDeAquecimentoGlobalUsoDoSoloEMudancaDeUsoDoSolo: 0.0246; PotencialDeEutrofizacaoFraccaoDeNutrientesQueAtingemOCompartimentoFinalDeAguaDoce: 0.000189; PotencialDeEutrofizacaoFraccaoDeNutrientesQueAtingemOCompartimentoFinalMarinho: 0.0122; EnergiaRecuperada: 0.00739; ConsumoDeAguaDoce: 0.113; UtilizacaoLiquidaDeAguaDoce: 0.113; ResiduosPerigososEliminados: 0.00221; ResiduosNaoPerigososEliminados: 1.83; MassaTotalDeResiduosRadioactivosEliminados: 0.000394; EnergiaElectricaExportada: 1.55; MateriaisParaRecuperacaoDeEnergia: 0.00739; MateriaisParaReciclagem: 0.0253; UnidadeEPD: 1 m²
Type - IFC.REVIGRÉS-Dados gerais-Wall Sweeps - Nome: REVIGRÉS-RULE-RB-8x60-SILK-SMOG; TipoProduto: Prensado a seco: grupo BIa UGL | Grés porcelânico técnico; NumeroDeRegistoDAP: EPD-REV-20240006-CCC1-EN; ReferenciaDAP: -; UrlDOP: -
Pset_BuildingElementProxyCommon - sets with these values: 2
Pset_ProvisionForVoid - Shape: Undefined; Width: 1000 mm; Depth: 1000 mm
IFC.REVIGRÉS-Dados do fabricante-Wall Sweeps - Type: Wall Sweep: REVIGRÉS-RULE-RB-8X60-SILK-SMOG
IFC.REVIGRÉS-Dados de desempenho-Wall Sweeps - Type: Wall Sweep: REVIGRÉS-RULE-RB-8X60-SILK-SMOG
IFC.REVIGRÉS-Dados de especificação-Wall Sweeps - Type: Wall Sweep: REVIGRÉS-RULE-RB-8X60-SILK-SMOG
IFC.REVIGRÉS-Dados geométricos-Wall Sweeps - Type: Wall Sweep: REVIGRÉS-RULE-RB-8X60-SILK-SMOG
IFC.REVIGRÉS-Dados de sustentabilidade-Wall Sweeps - Type: Wall Sweep: REVIGRÉS-RULE-RB-8X60-SILK-SMOG

# IfcBuildingElementProxy: Wall Sweep:REVIGRÉS-RULE-RB-8X60-SOFT GRIP-ALLOY, Wall Sweep:REVIGRÉS-RULE-RB-8X60-SOFT GRIP-ALLOY:180110
In: Level 1
Type - Pset_BuildingElementProxyCommon - Reference: REVIGRÉS-RULE-RB-8X60-SOFT GRIP-ALLOY
Type - Pset_ManufacturerTypeInformation - Manufacturer: REVIGRÉS
Type - Pset_ProductRequirements - Category: Wall Sweeps
Type - Pset_QuantityTakeOff - Reference: REVIGRÉS-RULE-RB-8X60-SOFT GRIP-ALLOY
Type - IFC.REVIGRÉS-Dados do fabricante-Wall Sweeps - FabricanteURL: https://www.revigres.pt/; ReferenciaModelo: Rule; Acabamento: SOFT GRIP; IdentificadorDoOperadorEconomico: 501840856; UrlFabricanteArtigo: https://www.revigres.pt/colecoes/rule; PaisOrigem: Portugal
Type - IFC.REVIGRÉS-Dados de desempenho-Wall Sweeps - Rectilinearidade: ± 0.2% máx.± 0.8 mm; Ortogonalidade: ± 0.2% máx.± 1.5 mm; PlanaridadeDaSuperficie: ± 0.3% máx. ± 1.8 mm; AbsorcaoDeAgua: < 0.05%; ModuloDeRuptura: > 45 N/mm²; ResistenciaAFlexao: >3500 N; ResistenciaAAbrasaoProfunda: < 120 mm³; DilatacaoTermicaLinear: ≤ 8,0x10-6 °C-1; ResistenciaAoChoqueTermico: Resiste; DurabilidadeResistenciaAoGeloDegelo: Resiste; ResistenciaAoEscorregamentoDIN51130: R11; ResistenciaAoEscorregamentoDIN51097: B; ResistenciaAoEscorregamentoENV51097: B; ResistenciaAoDeslizamentoENV12633: Class 2; ResistenciaAoEscorregamentoBS7976: >36; ResistenciaAoEscorregamentoANSIA1371: ≥0,42; ResistenciaAoEscorregamentoENV12633: Class 2; ResistenciaAoDeslizamentoBS7976: >36; ResistenciaAsManchas: Class 5; ResistenciaABaixasConcentracoesDeAcidosEAlcalis: Classe LA; ResistenciaAAltasConcentracoesDeAcidosEAlcalis: Classe HA; LibertacaoDeCadmio: 0; LibertacaoDeChumbo: 0
Type - IFC.REVIGRÉS-Dados de especificação-Wall Sweeps - VariacaoTonalidade: 3; NivelDeTrafego: 5; EPavimento: Não; ERevestimento: Sim; EExterno: Sim
Type - IFC.REVIGRÉS-Dados geométricos-Wall Sweeps - AlturaNominal: 10.5 mm; ComprimentoNominal: 8 mm; LarguraNominal: 59.2 mm
Type - IFC.REVIGRÉS-Dados de sustentabilidade-Wall Sweeps - ItemEParcialmenteReciclado: 0; PotencialPrivacaoDeAguaConsumoDeAguaPonderado: 4.5; EnergiaTermicaExportada: 0; ItemENovo: Sim; ItemEReciclado: Não; VidaÚtilEsperada: 50; SubstanciasPerigosas: Não; PotencialDeEsgotamentoAbioticoDosRecursosFosseis: 203; PotencialDeEsgotamentoAbioticoDosRecursosNaoFosseisMineraisEMetais: 0.000701; PotencialDeAquecimentoGlobalBiogenico: -0.48; CombustiveisFosseisComPotencialDeAquecimentoGlobal: 13.9; PotencialDeAquecimentoGlobalUsoDoSoloEMudancaDeUsoDoSolo: 0.0246; PotencialDeEutrofizacaoFraccaoDeNutrientesQueAtingemOCompartimentoFinalDeAguaDoce: 0.000189; PotencialDeEutrofizacaoFraccaoDeNutrientesQueAtingemOCompartimentoFinalMarinho: 0.0122; EnergiaRecuperada: 0.00739; ConsumoDeAguaDoce: 0.113; UtilizacaoLiquidaDeAguaDoce: 0.113; ResiduosPerigososEliminados: 0.00221; ResiduosNaoPerigososEliminados: 1.83; MassaTotalDeResiduosRadioactivosEliminados: 0.000394; EnergiaElectricaExportada: 1.55; MateriaisParaRecuperacaoDeEnergia: 0.00739; MateriaisParaReciclagem: 0.0253; UnidadeEPD: 1 m²
Type - IFC.REVIGRÉS-Dados gerais-Wall Sweeps - Nome: REVIGRÉS-RULE-RB-8x60-SOFT GRIP-ALLOY; TipoProduto: Prensado a seco: grupo BIa UGL | Grés porcelânico técnico; NumeroDeRegistoDAP: EPD-REV-20240006-CCC1-EN; ReferenciaDAP: -; UrlDOP: -
Pset_BuildingElementProxyCommon - sets with these values: 2
Pset_ProvisionForVoid - Shape: Undefined; Width: 1000 mm; Depth: 1000 mm
IFC.REVIGRÉS-Dados do fabricante-Wall Sweeps - Type: Wall Sweep: REVIGRÉS-RULE-RB-8X60-SOFT GRIP-ALLOY
IFC.REVIGRÉS-Dados de desempenho-Wall Sweeps - Type: Wall Sweep: REVIGRÉS-RULE-RB-8X60-SOFT GRIP-ALLOY
IFC.REVIGRÉS-Dados de especificação-Wall Sweeps - Type: Wall Sweep: REVIGRÉS-RULE-RB-8X60-SOFT GRIP-ALLOY
IFC.REVIGRÉS-Dados geométricos-Wall Sweeps - Type: Wall Sweep: REVIGRÉS-RULE-RB-8X60-SOFT GRIP-ALLOY
IFC.REVIGRÉS-Dados de sustentabilidade-Wall Sweeps - Type: Wall Sweep: REVIGRÉS-RULE-RB-8X60-SOFT GRIP-ALLOY

# IfcBuildingElementProxy: Wall Sweep:REVIGRÉS-RULE-RB-8X60-SOFT GRIP-SMOG, Wall Sweep:REVIGRÉS-RULE-RB-8X60-SOFT GRIP-SMOG:180115
In: Level 1
Type - Pset_BuildingElementProxyCommon - Reference: REVIGRÉS-RULE-RB-8X60-SOFT GRIP-SMOG
Type - Pset_ManufacturerTypeInformation - Manufacturer: REVIGRÉS
Type - Pset_ProductRequirements - Category: Wall Sweeps
Type - Pset_QuantityTakeOff - Reference: REVIGRÉS-RULE-RB-8X60-SOFT GRIP-SMOG
Type - IFC.REVIGRÉS-Dados do fabricante-Wall Sweeps - FabricanteURL: https://www.revigres.pt/; ReferenciaModelo: Rule; Acabamento: SOFT GRIP; IdentificadorDoOperadorEconomico: 501840856; UrlFabricanteArtigo: https://www.revigres.pt/colecoes/rule; PaisOrigem: Portugal
Type - IFC.REVIGRÉS-Dados de desempenho-Wall Sweeps - Rectilinearidade: ± 0.2% máx.± 0.8 mm; Ortogonalidade: ± 0.2% máx.± 1.5 mm; PlanaridadeDaSuperficie: ± 0.3% máx. ± 1.8 mm; AbsorcaoDeAgua: < 0.05%; ModuloDeRuptura: > 45 N/mm²; ResistenciaAFlexao: >3500 N; ResistenciaAAbrasaoProfunda: < 120 mm³; DilatacaoTermicaLinear: ≤ 8,0x10-6 °C-1; ResistenciaAoChoqueTermico: Resiste; DurabilidadeResistenciaAoGeloDegelo: Resiste; ResistenciaAoEscorregamentoDIN51130: R11; ResistenciaAoEscorregamentoDIN51097: B; ResistenciaAoEscorregamentoENV51097: B; ResistenciaAoDeslizamentoENV12633: Class 2; ResistenciaAoEscorregamentoBS7976: >36; ResistenciaAoEscorregamentoANSIA1371: ≥0,42; ResistenciaAoEscorregamentoENV12633: Class 2; ResistenciaAoDeslizamentoBS7976: >36; ResistenciaAsManchas: Class 5; ResistenciaABaixasConcentracoesDeAcidosEAlcalis: Classe LA; ResistenciaAAltasConcentracoesDeAcidosEAlcalis: Classe HA; LibertacaoDeCadmio: 0; LibertacaoDeChumbo: 0
Type - IFC.REVIGRÉS-Dados de especificação-Wall Sweeps - VariacaoTonalidade: 3; NivelDeTrafego: 5; EPavimento: Não; ERevestimento: Sim; EExterno: Sim
Type - IFC.REVIGRÉS-Dados geométricos-Wall Sweeps - AlturaNominal: 10.5 mm; ComprimentoNominal: 8 mm; LarguraNominal: 59.2 mm
Type - IFC.REVIGRÉS-Dados de sustentabilidade-Wall Sweeps - PotencialPrivacaoDeAguaConsumoDeAguaPonderado: 4.5; EnergiaTermicaExportada: 0; ItemENovo: Sim; ItemEParcialmenteReciclado: 0.23; ItemEReciclado: Sim; VidaÚtilEsperada: 50; SubstanciasPerigosas: Não; PotencialDeEsgotamentoAbioticoDosRecursosFosseis: 203; PotencialDeEsgotamentoAbioticoDosRecursosNaoFosseisMineraisEMetais: 0.000701; PotencialDeAquecimentoGlobalBiogenico: -0.48; CombustiveisFosseisComPotencialDeAquecimentoGlobal: 13.9; PotencialDeAquecimentoGlobalUsoDoSoloEMudancaDeUsoDoSolo: 0.0246; PotencialDeEutrofizacaoFraccaoDeNutrientesQueAtingemOCompartimentoFinalDeAguaDoce: 0.000189; PotencialDeEutrofizacaoFraccaoDeNutrientesQueAtingemOCompartimentoFinalMarinho: 0.0122; EnergiaRecuperada: 0.00739; ConsumoDeAguaDoce: 0.113; UtilizacaoLiquidaDeAguaDoce: 0.113; ResiduosPerigososEliminados: 0.00221; ResiduosNaoPerigososEliminados: 1.83; MassaTotalDeResiduosRadioactivosEliminados: 0.000394; EnergiaElectricaExportada: 1.55; MateriaisParaRecuperacaoDeEnergia: 0.00739; MateriaisParaReciclagem: 0.0253; UnidadeEPD: 1 m²
Type - IFC.REVIGRÉS-Dados gerais-Wall Sweeps - Nome: REVIGRÉS-RULE-RB-8x60-SOFT GRIP-SMOG; TipoProduto: Prensado a seco: grupo BIa UGL | Grés porcelânico técnico; NumeroDeRegistoDAP: EPD-REV-20240006-CCC1-EN; ReferenciaDAP: -; UrlDOP: -
Pset_BuildingElementProxyCommon - sets with these values: 2
Pset_ProvisionForVoid - Shape: Undefined; Width: 1000 mm; Depth: 1000 mm
IFC.REVIGRÉS-Dados do fabricante-Wall Sweeps - Type: Wall Sweep: REVIGRÉS-RULE-RB-8X60-SOFT GRIP-SMOG
IFC.REVIGRÉS-Dados de desempenho-Wall Sweeps - Type: Wall Sweep: REVIGRÉS-RULE-RB-8X60-SOFT GRIP-SMOG
IFC.REVIGRÉS-Dados de especificação-Wall Sweeps - Type: Wall Sweep: REVIGRÉS-RULE-RB-8X60-SOFT GRIP-SMOG
IFC.REVIGRÉS-Dados geométricos-Wall Sweeps - Type: Wall Sweep: REVIGRÉS-RULE-RB-8X60-SOFT GRIP-SMOG
IFC.REVIGRÉS-Dados de sustentabilidade-Wall Sweeps - Type: Wall Sweep: REVIGRÉS-RULE-RB-8X60-SOFT GRIP-SMOG

# IfcBuildingElementProxy: Wall Sweep:REVIGRÉS-RULE-RB-8X90-SILK-ALLOY, Wall Sweep:REVIGRÉS-RULE-RB-8X90-SILK-ALLOY:180123
In: Level 1
Type - Pset_BuildingElementProxyCommon - Reference: REVIGRÉS-RULE-RB-8X90-SILK-ALLOY
Type - Pset_ManufacturerTypeInformation - Manufacturer: REVIGRÉS
Type - Pset_ProductRequirements - Category: Wall Sweeps
Type - Pset_QuantityTakeOff - Reference: REVIGRÉS-RULE-RB-8X90-SILK-ALLOY
Type - IFC.REVIGRÉS-Dados do fabricante-Wall Sweeps - FabricanteURL: https://www.revigres.pt/; ReferenciaModelo: Rule; Acabamento: SILK; IdentificadorDoOperadorEconomico: 501840856; UrlFabricanteArtigo: https://www.revigres.pt/colecoes/rule; PaisOrigem: Portugal
Type - IFC.REVIGRÉS-Dados de desempenho-Wall Sweeps - Rectilinearidade: ± 0.2% máx.± 0.8 mm; Ortogonalidade: ± 0.2% máx.± 1.5 mm; PlanaridadeDaSuperficie: ± 0.3% máx. ± 1.8 mm; AbsorcaoDeAgua: < 0.05%; ModuloDeRuptura: > 45 N/mm²; ResistenciaAFlexao: >3500 N; ResistenciaAAbrasaoProfunda: < 120 mm³; DilatacaoTermicaLinear: ≤ 8,0x10-6 °C-1; ResistenciaAoChoqueTermico: Resiste; DurabilidadeResistenciaAoGeloDegelo: Resiste; ResistenciaAoEscorregamentoDIN51130: R9; ResistenciaAoEscorregamentoDIN51097: A; ResistenciaAoEscorregamentoENV51097: A; ResistenciaAoDeslizamentoENV12633: Class 1; ResistenciaAoEscorregamentoANSIA1371: ≥0,42; ResistenciaAoEscorregamentoENV12633: Class 1; ResistenciaAsManchas: Class 5; ResistenciaABaixasConcentracoesDeAcidosEAlcalis: Classe LA; ResistenciaAAltasConcentracoesDeAcidosEAlcalis: Classe HA; LibertacaoDeCadmio: 0; LibertacaoDeChumbo: 0
Type - IFC.REVIGRÉS-Dados de especificação-Wall Sweeps - VariacaoTonalidade: 3; NivelDeTrafego: 5; EPavimento: Não; ERevestimento: Sim; EExterno: Sim
Type - IFC.REVIGRÉS-Dados geométricos-Wall Sweeps - AlturaNominal: 10.5 mm; ComprimentoNominal: 8 mm; LarguraNominal: 88.9 mm
Type - IFC.REVIGRÉS-Dados de sustentabilidade-Wall Sweeps - ItemEParcialmenteReciclado: 0; PotencialPrivacaoDeAguaConsumoDeAguaPonderado: 4.5; EnergiaTermicaExportada: 0; ItemENovo: Sim; ItemEReciclado: Não; VidaÚtilEsperada: 50; SubstanciasPerigosas: Não; PotencialDeEsgotamentoAbioticoDosRecursosFosseis: 203; PotencialDeEsgotamentoAbioticoDosRecursosNaoFosseisMineraisEMetais: 0.000701; PotencialDeAquecimentoGlobalBiogenico: -0.48; CombustiveisFosseisComPotencialDeAquecimentoGlobal: 13.9; PotencialDeAquecimentoGlobalUsoDoSoloEMudancaDeUsoDoSolo: 0.0246; PotencialDeEutrofizacaoFraccaoDeNutrientesQueAtingemOCompartimentoFinalDeAguaDoce: 0.000189; PotencialDeEutrofizacaoFraccaoDeNutrientesQueAtingemOCompartimentoFinalMarinho: 0.0122; EnergiaRecuperada: 0.00739; ConsumoDeAguaDoce: 0.113; UtilizacaoLiquidaDeAguaDoce: 0.113; ResiduosPerigososEliminados: 0.00221; ResiduosNaoPerigososEliminados: 1.83; MassaTotalDeResiduosRadioactivosEliminados: 0.000394; EnergiaElectricaExportada: 1.55; MateriaisParaRecuperacaoDeEnergia: 0.00739; MateriaisParaReciclagem: 0.0253; UnidadeEPD: 1 m²
Type - IFC.REVIGRÉS-Dados gerais-Wall Sweeps - Nome: REVIGRÉS-RULE-RB-8x90-SILK-ALLOY; TipoProduto: Prensado a seco: grupo BIa UGL | Grés porcelânico técnico; NumeroDeRegistoDAP: EPD-REV-20240006-CCC1-EN; ReferenciaDAP: -; UrlDOP: -
Pset_BuildingElementProxyCommon - sets with these values: 2
Pset_ProvisionForVoid - Shape: Undefined; Width: 1000 mm; Depth: 1000 mm
IFC.REVIGRÉS-Dados do fabricante-Wall Sweeps - Type: Wall Sweep: REVIGRÉS-RULE-RB-8X90-SILK-ALLOY
IFC.REVIGRÉS-Dados de desempenho-Wall Sweeps - Type: Wall Sweep: REVIGRÉS-RULE-RB-8X90-SILK-ALLOY
IFC.REVIGRÉS-Dados de especificação-Wall Sweeps - Type: Wall Sweep: REVIGRÉS-RULE-RB-8X90-SILK-ALLOY
IFC.REVIGRÉS-Dados geométricos-Wall Sweeps - Type: Wall Sweep: REVIGRÉS-RULE-RB-8X90-SILK-ALLOY
IFC.REVIGRÉS-Dados de sustentabilidade-Wall Sweeps - Type: Wall Sweep: REVIGRÉS-RULE-RB-8X90-SILK-ALLOY

# IfcBuildingElementProxy: Wall Sweep:REVIGRÉS-RULE-RB-8X90-SILK-SMOG, Wall Sweep:REVIGRÉS-RULE-RB-8X90-SILK-SMOG:180130
In: Level 1
Type - Pset_BuildingElementProxyCommon - Reference: REVIGRÉS-RULE-RB-8X90-SILK-SMOG
Type - Pset_ManufacturerTypeInformation - Manufacturer: REVIGRÉS
Type - Pset_ProductRequirements - Category: Wall Sweeps
Type - Pset_QuantityTakeOff - Reference: REVIGRÉS-RULE-RB-8X90-SILK-SMOG
Type - IFC.REVIGRÉS-Dados do fabricante-Wall Sweeps - FabricanteURL: https://www.revigres.pt/; ReferenciaModelo: Rule; Acabamento: SILK; IdentificadorDoOperadorEconomico: 501840856; UrlFabricanteArtigo: https://www.revigres.pt/colecoes/rule; PaisOrigem: Portugal
Type - IFC.REVIGRÉS-Dados de desempenho-Wall Sweeps - Rectilinearidade: ± 0.2% máx.± 0.8 mm; Ortogonalidade: ± 0.2% máx.± 1.5 mm; PlanaridadeDaSuperficie: ± 0.3% máx. ± 1.8 mm; AbsorcaoDeAgua: < 0.05%; ModuloDeRuptura: > 45 N/mm²; ResistenciaAFlexao: >3500 N; ResistenciaAAbrasaoProfunda: < 120 mm³; DilatacaoTermicaLinear: ≤ 8,0x10-6 °C-1; ResistenciaAoChoqueTermico: Resiste; DurabilidadeResistenciaAoGeloDegelo: Resiste; ResistenciaAoEscorregamentoDIN51130: R9; ResistenciaAoEscorregamentoDIN51097: A; ResistenciaAoEscorregamentoENV51097: A; ResistenciaAoDeslizamentoENV12633: Class 1; ResistenciaAoEscorregamentoANSIA1371: ≥0,42; ResistenciaAoEscorregamentoENV12633: Class 1; ResistenciaAsManchas: Class 5; ResistenciaABaixasConcentracoesDeAcidosEAlcalis: Classe LA; ResistenciaAAltasConcentracoesDeAcidosEAlcalis: Classe HA; LibertacaoDeCadmio: 0; LibertacaoDeChumbo: 0
Type - IFC.REVIGRÉS-Dados de especificação-Wall Sweeps - VariacaoTonalidade: 3; NivelDeTrafego: 5; EPavimento: Não; ERevestimento: Sim; EExterno: Sim
Type - IFC.REVIGRÉS-Dados geométricos-Wall Sweeps - AlturaNominal: 10.5 mm; ComprimentoNominal: 8 mm; LarguraNominal: 88.9 mm
Type - IFC.REVIGRÉS-Dados de sustentabilidade-Wall Sweeps - PotencialPrivacaoDeAguaConsumoDeAguaPonderado: 4.5; EnergiaTermicaExportada: 0; ItemENovo: Sim; ItemEParcialmenteReciclado: 0.23; ItemEReciclado: Sim; VidaÚtilEsperada: 50; SubstanciasPerigosas: Não; PotencialDeEsgotamentoAbioticoDosRecursosFosseis: 203; PotencialDeEsgotamentoAbioticoDosRecursosNaoFosseisMineraisEMetais: 0.000701; PotencialDeAquecimentoGlobalBiogenico: -0.48; CombustiveisFosseisComPotencialDeAquecimentoGlobal: 13.9; PotencialDeAquecimentoGlobalUsoDoSoloEMudancaDeUsoDoSolo: 0.0246; PotencialDeEutrofizacaoFraccaoDeNutrientesQueAtingemOCompartimentoFinalDeAguaDoce: 0.000189; PotencialDeEutrofizacaoFraccaoDeNutrientesQueAtingemOCompartimentoFinalMarinho: 0.0122; EnergiaRecuperada: 0.00739; ConsumoDeAguaDoce: 0.113; UtilizacaoLiquidaDeAguaDoce: 0.113; ResiduosPerigososEliminados: 0.00221; ResiduosNaoPerigososEliminados: 1.83; MassaTotalDeResiduosRadioactivosEliminados: 0.000394; EnergiaElectricaExportada: 1.55; MateriaisParaRecuperacaoDeEnergia: 0.00739; MateriaisParaReciclagem: 0.0253; UnidadeEPD: 1 m²
Type - IFC.REVIGRÉS-Dados gerais-Wall Sweeps - Nome: REVIGRÉS-RULE-RB-8x90-SILK-SMOG; TipoProduto: Prensado a seco: grupo BIa UGL | Grés porcelânico técnico; NumeroDeRegistoDAP: EPD-REV-20240006-CCC1-EN; ReferenciaDAP: -; UrlDOP: -
Pset_BuildingElementProxyCommon - sets with these values: 2
Pset_ProvisionForVoid - Shape: Undefined; Width: 1000 mm; Depth: 1000 mm
IFC.REVIGRÉS-Dados do fabricante-Wall Sweeps - Type: Wall Sweep: REVIGRÉS-RULE-RB-8X90-SILK-SMOG
IFC.REVIGRÉS-Dados de desempenho-Wall Sweeps - Type: Wall Sweep: REVIGRÉS-RULE-RB-8X90-SILK-SMOG
IFC.REVIGRÉS-Dados de especificação-Wall Sweeps - Type: Wall Sweep: REVIGRÉS-RULE-RB-8X90-SILK-SMOG
IFC.REVIGRÉS-Dados geométricos-Wall Sweeps - Type: Wall Sweep: REVIGRÉS-RULE-RB-8X90-SILK-SMOG
IFC.REVIGRÉS-Dados de sustentabilidade-Wall Sweeps - Type: Wall Sweep: REVIGRÉS-RULE-RB-8X90-SILK-SMOG

# IfcBuildingElementProxy: Wall Sweep:REVIGRÉS-RULE-RB-8X90-SOFT GRIP-ALLOY, Wall Sweep:REVIGRÉS-RULE-RB-8X90-SOFT GRIP-ALLOY:180111
In: Level 1
Type - Pset_BuildingElementProxyCommon - Reference: REVIGRÉS-RULE-RB-8X90-SOFT GRIP-ALLOY
Type - Pset_ManufacturerTypeInformation - Manufacturer: REVIGRÉS
Type - Pset_ProductRequirements - Category: Wall Sweeps
Type - Pset_QuantityTakeOff - Reference: REVIGRÉS-RULE-RB-8X90-SOFT GRIP-ALLOY
Type - IFC.REVIGRÉS-Dados do fabricante-Wall Sweeps - FabricanteURL: https://www.revigres.pt/; ReferenciaModelo: Rule; Acabamento: SOFT GRIP; IdentificadorDoOperadorEconomico: 501840856; UrlFabricanteArtigo: https://www.revigres.pt/colecoes/rule; PaisOrigem: Portugal
Type - IFC.REVIGRÉS-Dados de desempenho-Wall Sweeps - Rectilinearidade: ± 0.2% máx.± 0.8 mm; Ortogonalidade: ± 0.2% máx.± 1.5 mm; PlanaridadeDaSuperficie: ± 0.3% máx. ± 1.8 mm; AbsorcaoDeAgua: < 0.05%; ModuloDeRuptura: > 45 N/mm²; ResistenciaAFlexao: >3500 N; ResistenciaAAbrasaoProfunda: < 120 mm³; DilatacaoTermicaLinear: ≤ 8,0x10-6 °C-1; ResistenciaAoChoqueTermico: Resiste; DurabilidadeResistenciaAoGeloDegelo: Resiste; ResistenciaAoEscorregamentoDIN51130: R11; ResistenciaAoEscorregamentoDIN51097: B; ResistenciaAoEscorregamentoENV51097: B; ResistenciaAoDeslizamentoENV12633: Class 2; ResistenciaAoEscorregamentoBS7976: >36; ResistenciaAoEscorregamentoANSIA1371: ≥0,42; ResistenciaAoEscorregamentoENV12633: Class 2; ResistenciaAoDeslizamentoBS7976: >36; ResistenciaAsManchas: Class 5; ResistenciaABaixasConcentracoesDeAcidosEAlcalis: Classe LA; ResistenciaAAltasConcentracoesDeAcidosEAlcalis: Classe HA; LibertacaoDeCadmio: 0; LibertacaoDeChumbo: 0
Type - IFC.REVIGRÉS-Dados de especificação-Wall Sweeps - VariacaoTonalidade: 3; NivelDeTrafego: 5; EPavimento: Não; ERevestimento: Sim; EExterno: Sim
Type - IFC.REVIGRÉS-Dados geométricos-Wall Sweeps - AlturaNominal: 10.5 mm; ComprimentoNominal: 8 mm; LarguraNominal: 88.9 mm
Type - IFC.REVIGRÉS-Dados de sustentabilidade-Wall Sweeps - ItemEParcialmenteReciclado: 0; PotencialPrivacaoDeAguaConsumoDeAguaPonderado: 4.5; EnergiaTermicaExportada: 0; ItemENovo: Sim; ItemEReciclado: Não; VidaÚtilEsperada: 50; SubstanciasPerigosas: Não; PotencialDeEsgotamentoAbioticoDosRecursosFosseis: 203; PotencialDeEsgotamentoAbioticoDosRecursosNaoFosseisMineraisEMetais: 0.000701; PotencialDeAquecimentoGlobalBiogenico: -0.48; CombustiveisFosseisComPotencialDeAquecimentoGlobal: 13.9; PotencialDeAquecimentoGlobalUsoDoSoloEMudancaDeUsoDoSolo: 0.0246; PotencialDeEutrofizacaoFraccaoDeNutrientesQueAtingemOCompartimentoFinalDeAguaDoce: 0.000189; PotencialDeEutrofizacaoFraccaoDeNutrientesQueAtingemOCompartimentoFinalMarinho: 0.0122; EnergiaRecuperada: 0.00739; ConsumoDeAguaDoce: 0.113; UtilizacaoLiquidaDeAguaDoce: 0.113; ResiduosPerigososEliminados: 0.00221; ResiduosNaoPerigososEliminados: 1.83; MassaTotalDeResiduosRadioactivosEliminados: 0.000394; EnergiaElectricaExportada: 1.55; MateriaisParaRecuperacaoDeEnergia: 0.00739; MateriaisParaReciclagem: 0.0253; UnidadeEPD: 1 m²
Type - IFC.REVIGRÉS-Dados gerais-Wall Sweeps - Nome: REVIGRÉS-RULE-RB-8x90-SOFT GRIP-ALLOY; TipoProduto: Prensado a seco: grupo BIa UGL | Grés porcelânico técnico; NumeroDeRegistoDAP: EPD-REV-20240006-CCC1-EN; ReferenciaDAP: -; UrlDOP: -
Pset_BuildingElementProxyCommon - sets with these values: 2
Pset_ProvisionForVoid - Shape: Undefined; Width: 1000 mm; Depth: 1000 mm
IFC.REVIGRÉS-Dados do fabricante-Wall Sweeps - Type: Wall Sweep: REVIGRÉS-RULE-RB-8X90-SOFT GRIP-ALLOY
IFC.REVIGRÉS-Dados de desempenho-Wall Sweeps - Type: Wall Sweep: REVIGRÉS-RULE-RB-8X90-SOFT GRIP-ALLOY
IFC.REVIGRÉS-Dados de especificação-Wall Sweeps - Type: Wall Sweep: REVIGRÉS-RULE-RB-8X90-SOFT GRIP-ALLOY
IFC.REVIGRÉS-Dados geométricos-Wall Sweeps - Type: Wall Sweep: REVIGRÉS-RULE-RB-8X90-SOFT GRIP-ALLOY
IFC.REVIGRÉS-Dados de sustentabilidade-Wall Sweeps - Type: Wall Sweep: REVIGRÉS-RULE-RB-8X90-SOFT GRIP-ALLOY

# IfcBuildingElementProxy: Wall Sweep:REVIGRÉS-RULE-RB-8X90-SOFT GRIP-SMOG, Wall Sweep:REVIGRÉS-RULE-RB-8X90-SOFT GRIP-SMOG:180116
In: Level 1
Type - Pset_BuildingElementProxyCommon - Reference: REVIGRÉS-RULE-RB-8X90-SOFT GRIP-SMOG
Type - Pset_ManufacturerTypeInformation - Manufacturer: REVIGRÉS
Type - Pset_ProductRequirements - Category: Wall Sweeps
Type - Pset_QuantityTakeOff - Reference: REVIGRÉS-RULE-RB-8X90-SOFT GRIP-SMOG
Type - IFC.REVIGRÉS-Dados do fabricante-Wall Sweeps - FabricanteURL: https://www.revigres.pt/; ReferenciaModelo: Rule; Acabamento: SOFT GRIP; IdentificadorDoOperadorEconomico: 501840856; UrlFabricanteArtigo: https://www.revigres.pt/colecoes/rule; PaisOrigem: Portugal
